VERSION 5.7 ;
  NOWIREEXTENSIONATPIN ON ;
  DIVIDERCHAR "/" ;
  BUSBITCHARS "[]" ;
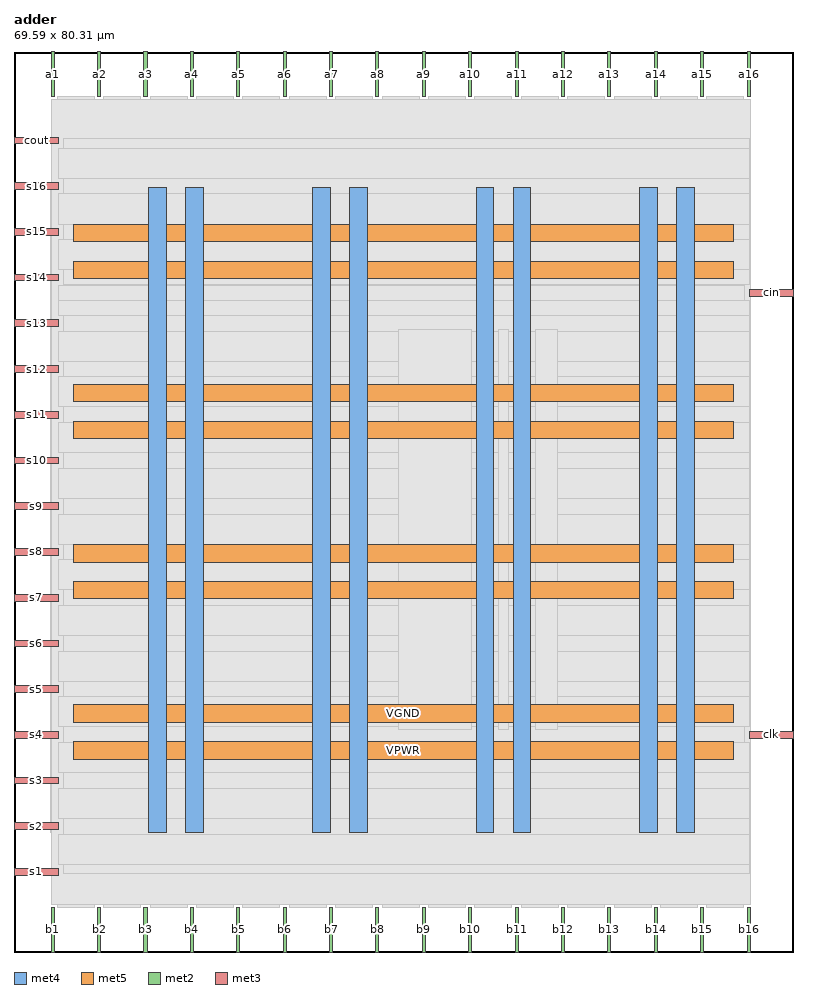
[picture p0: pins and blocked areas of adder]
MACRO adder
  CLASS BLOCK ;
  FOREIGN adder ;
  ORIGIN 0.000 0.000 ;
  SIZE 69.590 BY 80.310 ;
  PIN VGND
    DIRECTION INOUT ;
    USE GROUND ;
    PORT
      LAYER met4 ;
        RECT 15.320 10.640 16.920 68.240 ;
    END
    PORT
      LAYER met4 ;
        RECT 29.925 10.640 31.525 68.240 ;
    END
    PORT
      LAYER met4 ;
        RECT 44.530 10.640 46.130 68.240 ;
    END
    PORT
      LAYER met4 ;
        RECT 59.135 10.640 60.735 68.240 ;
    END
    PORT
      LAYER met5 ;
        RECT 5.280 20.520 64.180 22.120 ;
    END
    PORT
      LAYER met5 ;
        RECT 5.280 34.800 64.180 36.400 ;
    END
    PORT
      LAYER met5 ;
        RECT 5.280 49.080 64.180 50.680 ;
    END
    PORT
      LAYER met5 ;
        RECT 5.280 63.360 64.180 64.960 ;
    END
  END VGND
  PIN VPWR
    DIRECTION INOUT ;
    USE POWER ;
    PORT
      LAYER met4 ;
        RECT 12.020 10.640 13.620 68.240 ;
    END
    PORT
      LAYER met4 ;
        RECT 26.625 10.640 28.225 68.240 ;
    END
    PORT
      LAYER met4 ;
        RECT 41.230 10.640 42.830 68.240 ;
    END
    PORT
      LAYER met4 ;
        RECT 55.835 10.640 57.435 68.240 ;
    END
    PORT
      LAYER met5 ;
        RECT 5.280 17.220 64.180 18.820 ;
    END
    PORT
      LAYER met5 ;
        RECT 5.280 31.500 64.180 33.100 ;
    END
    PORT
      LAYER met5 ;
        RECT 5.280 45.780 64.180 47.380 ;
    END
    PORT
      LAYER met5 ;
        RECT 5.280 60.060 64.180 61.660 ;
    END
  END VPWR
  PIN a1
    DIRECTION INPUT ;
    USE SIGNAL ;
    ANTENNAGATEAREA 0.196500 ;
    PORT
      LAYER met2 ;
        RECT 3.310 76.310 3.590 80.310 ;
    END
  END a1
  PIN a10
    DIRECTION INPUT ;
    USE SIGNAL ;
    ANTENNAGATEAREA 0.196500 ;
    PORT
      LAYER met2 ;
        RECT 40.570 76.310 40.850 80.310 ;
    END
  END a10
  PIN a11
    DIRECTION INPUT ;
    USE SIGNAL ;
    ANTENNAGATEAREA 0.196500 ;
    PORT
      LAYER met2 ;
        RECT 44.710 76.310 44.990 80.310 ;
    END
  END a11
  PIN a12
    DIRECTION INPUT ;
    USE SIGNAL ;
    ANTENNAGATEAREA 0.196500 ;
    PORT
      LAYER met2 ;
        RECT 48.850 76.310 49.130 80.310 ;
    END
  END a12
  PIN a13
    DIRECTION INPUT ;
    USE SIGNAL ;
    ANTENNAGATEAREA 0.196500 ;
    PORT
      LAYER met2 ;
        RECT 52.990 76.310 53.270 80.310 ;
    END
  END a13
  PIN a14
    DIRECTION INPUT ;
    USE SIGNAL ;
    ANTENNAGATEAREA 0.196500 ;
    PORT
      LAYER met2 ;
        RECT 57.130 76.310 57.410 80.310 ;
    END
  END a14
  PIN a15
    DIRECTION INPUT ;
    USE SIGNAL ;
    ANTENNAGATEAREA 0.196500 ;
    PORT
      LAYER met2 ;
        RECT 61.270 76.310 61.550 80.310 ;
    END
  END a15
  PIN a16
    DIRECTION INPUT ;
    USE SIGNAL ;
    ANTENNAGATEAREA 0.196500 ;
    PORT
      LAYER met2 ;
        RECT 65.410 76.310 65.690 80.310 ;
    END
  END a16
  PIN a2
    DIRECTION INPUT ;
    USE SIGNAL ;
    ANTENNAGATEAREA 0.196500 ;
    PORT
      LAYER met2 ;
        RECT 7.450 76.310 7.730 80.310 ;
    END
  END a2
  PIN a3
    DIRECTION INPUT ;
    USE SIGNAL ;
    ANTENNAGATEAREA 0.196500 ;
    PORT
      LAYER met2 ;
        RECT 11.590 76.310 11.870 80.310 ;
    END
  END a3
  PIN a4
    DIRECTION INPUT ;
    USE SIGNAL ;
    ANTENNAGATEAREA 0.196500 ;
    PORT
      LAYER met2 ;
        RECT 15.730 76.310 16.010 80.310 ;
    END
  END a4
  PIN a5
    DIRECTION INPUT ;
    USE SIGNAL ;
    ANTENNAGATEAREA 0.196500 ;
    PORT
      LAYER met2 ;
        RECT 19.870 76.310 20.150 80.310 ;
    END
  END a5
  PIN a6
    DIRECTION INPUT ;
    USE SIGNAL ;
    ANTENNAGATEAREA 0.196500 ;
    PORT
      LAYER met2 ;
        RECT 24.010 76.310 24.290 80.310 ;
    END
  END a6
  PIN a7
    DIRECTION INPUT ;
    USE SIGNAL ;
    ANTENNAGATEAREA 0.196500 ;
    PORT
      LAYER met2 ;
        RECT 28.150 76.310 28.430 80.310 ;
    END
  END a7
  PIN a8
    DIRECTION INPUT ;
    USE SIGNAL ;
    ANTENNAGATEAREA 0.196500 ;
    PORT
      LAYER met2 ;
        RECT 32.290 76.310 32.570 80.310 ;
    END
  END a8
  PIN a9
    DIRECTION INPUT ;
    USE SIGNAL ;
    ANTENNAGATEAREA 0.196500 ;
    PORT
      LAYER met2 ;
        RECT 36.430 76.310 36.710 80.310 ;
    END
  END a9
  PIN b1
    DIRECTION INPUT ;
    USE SIGNAL ;
    ANTENNAGATEAREA 0.196500 ;
    PORT
      LAYER met2 ;
        RECT 3.310 0.000 3.590 4.000 ;
    END
  END b1
  PIN b10
    DIRECTION INPUT ;
    USE SIGNAL ;
    ANTENNAGATEAREA 0.196500 ;
    PORT
      LAYER met2 ;
        RECT 40.570 0.000 40.850 4.000 ;
    END
  END b10
  PIN b11
    DIRECTION INPUT ;
    USE SIGNAL ;
    ANTENNAGATEAREA 0.196500 ;
    PORT
      LAYER met2 ;
        RECT 44.710 0.000 44.990 4.000 ;
    END
  END b11
  PIN b12
    DIRECTION INPUT ;
    USE SIGNAL ;
    ANTENNAGATEAREA 0.196500 ;
    PORT
      LAYER met2 ;
        RECT 48.850 0.000 49.130 4.000 ;
    END
  END b12
  PIN b13
    DIRECTION INPUT ;
    USE SIGNAL ;
    ANTENNAGATEAREA 0.196500 ;
    PORT
      LAYER met2 ;
        RECT 52.990 0.000 53.270 4.000 ;
    END
  END b13
  PIN b14
    DIRECTION INPUT ;
    USE SIGNAL ;
    ANTENNAGATEAREA 0.196500 ;
    PORT
      LAYER met2 ;
        RECT 57.130 0.000 57.410 4.000 ;
    END
  END b14
  PIN b15
    DIRECTION INPUT ;
    USE SIGNAL ;
    ANTENNAGATEAREA 0.196500 ;
    PORT
      LAYER met2 ;
        RECT 61.270 0.000 61.550 4.000 ;
    END
  END b15
  PIN b16
    DIRECTION INPUT ;
    USE SIGNAL ;
    ANTENNAGATEAREA 0.196500 ;
    PORT
      LAYER met2 ;
        RECT 65.410 0.000 65.690 4.000 ;
    END
  END b16
  PIN b2
    DIRECTION INPUT ;
    USE SIGNAL ;
    ANTENNAGATEAREA 0.196500 ;
    PORT
      LAYER met2 ;
        RECT 7.450 0.000 7.730 4.000 ;
    END
  END b2
  PIN b3
    DIRECTION INPUT ;
    USE SIGNAL ;
    ANTENNAGATEAREA 0.196500 ;
    PORT
      LAYER met2 ;
        RECT 11.590 0.000 11.870 4.000 ;
    END
  END b3
  PIN b4
    DIRECTION INPUT ;
    USE SIGNAL ;
    ANTENNAGATEAREA 0.196500 ;
    PORT
      LAYER met2 ;
        RECT 15.730 0.000 16.010 4.000 ;
    END
  END b4
  PIN b5
    DIRECTION INPUT ;
    USE SIGNAL ;
    ANTENNAGATEAREA 0.196500 ;
    PORT
      LAYER met2 ;
        RECT 19.870 0.000 20.150 4.000 ;
    END
  END b5
  PIN b6
    DIRECTION INPUT ;
    USE SIGNAL ;
    ANTENNAGATEAREA 0.196500 ;
    PORT
      LAYER met2 ;
        RECT 24.010 0.000 24.290 4.000 ;
    END
  END b6
  PIN b7
    DIRECTION INPUT ;
    USE SIGNAL ;
    ANTENNAGATEAREA 0.196500 ;
    PORT
      LAYER met2 ;
        RECT 28.150 0.000 28.430 4.000 ;
    END
  END b7
  PIN b8
    DIRECTION INPUT ;
    USE SIGNAL ;
    ANTENNAGATEAREA 0.196500 ;
    PORT
      LAYER met2 ;
        RECT 32.290 0.000 32.570 4.000 ;
    END
  END b8
  PIN b9
    DIRECTION INPUT ;
    USE SIGNAL ;
    ANTENNAGATEAREA 0.196500 ;
    PORT
      LAYER met2 ;
        RECT 36.430 0.000 36.710 4.000 ;
    END
  END b9
  PIN cin
    DIRECTION INPUT ;
    USE SIGNAL ;
    ANTENNAGATEAREA 0.196500 ;
    PORT
      LAYER met3 ;
        RECT 65.590 58.520 69.590 59.120 ;
    END
  END cin
  PIN clk
    DIRECTION INPUT ;
    USE SIGNAL ;
    ANTENNAGATEAREA 0.852000 ;
    PORT
      LAYER met3 ;
        RECT 65.590 19.080 69.590 19.680 ;
    END
  END clk
  PIN cout
    DIRECTION OUTPUT ;
    USE SIGNAL ;
    ANTENNADIFFAREA 0.340600 ;
    PORT
      LAYER met3 ;
        RECT 0.000 72.120 4.000 72.720 ;
    END
  END cout
  PIN s1
    DIRECTION OUTPUT ;
    USE SIGNAL ;
    ANTENNADIFFAREA 0.340600 ;
    PORT
      LAYER met3 ;
        RECT 0.000 6.840 4.000 7.440 ;
    END
  END s1
  PIN s10
    DIRECTION OUTPUT ;
    USE SIGNAL ;
    ANTENNADIFFAREA 0.340600 ;
    PORT
      LAYER met3 ;
        RECT 0.000 43.560 4.000 44.160 ;
    END
  END s10
  PIN s11
    DIRECTION OUTPUT ;
    USE SIGNAL ;
    ANTENNADIFFAREA 0.340600 ;
    PORT
      LAYER met3 ;
        RECT 0.000 47.640 4.000 48.240 ;
    END
  END s11
  PIN s12
    DIRECTION OUTPUT ;
    USE SIGNAL ;
    ANTENNADIFFAREA 0.340600 ;
    PORT
      LAYER met3 ;
        RECT 0.000 51.720 4.000 52.320 ;
    END
  END s12
  PIN s13
    DIRECTION OUTPUT ;
    USE SIGNAL ;
    ANTENNADIFFAREA 0.340600 ;
    PORT
      LAYER met3 ;
        RECT 0.000 55.800 4.000 56.400 ;
    END
  END s13
  PIN s14
    DIRECTION OUTPUT ;
    USE SIGNAL ;
    ANTENNADIFFAREA 0.340600 ;
    PORT
      LAYER met3 ;
        RECT 0.000 59.880 4.000 60.480 ;
    END
  END s14
  PIN s15
    DIRECTION OUTPUT ;
    USE SIGNAL ;
    ANTENNADIFFAREA 0.340600 ;
    PORT
      LAYER met3 ;
        RECT 0.000 63.960 4.000 64.560 ;
    END
  END s15
  PIN s16
    DIRECTION OUTPUT ;
    USE SIGNAL ;
    ANTENNADIFFAREA 0.340600 ;
    PORT
      LAYER met3 ;
        RECT 0.000 68.040 4.000 68.640 ;
    END
  END s16
  PIN s2
    DIRECTION OUTPUT ;
    USE SIGNAL ;
    ANTENNADIFFAREA 0.340600 ;
    PORT
      LAYER met3 ;
        RECT 0.000 10.920 4.000 11.520 ;
    END
  END s2
  PIN s3
    DIRECTION OUTPUT ;
    USE SIGNAL ;
    ANTENNADIFFAREA 0.340600 ;
    PORT
      LAYER met3 ;
        RECT 0.000 15.000 4.000 15.600 ;
    END
  END s3
  PIN s4
    DIRECTION OUTPUT ;
    USE SIGNAL ;
    ANTENNADIFFAREA 0.340600 ;
    PORT
      LAYER met3 ;
        RECT 0.000 19.080 4.000 19.680 ;
    END
  END s4
  PIN s5
    DIRECTION OUTPUT ;
    USE SIGNAL ;
    ANTENNADIFFAREA 0.340600 ;
    PORT
      LAYER met3 ;
        RECT 0.000 23.160 4.000 23.760 ;
    END
  END s5
  PIN s6
    DIRECTION OUTPUT ;
    USE SIGNAL ;
    ANTENNADIFFAREA 0.340600 ;
    PORT
      LAYER met3 ;
        RECT 0.000 27.240 4.000 27.840 ;
    END
  END s6
  PIN s7
    DIRECTION OUTPUT ;
    USE SIGNAL ;
    ANTENNADIFFAREA 0.340600 ;
    PORT
      LAYER met3 ;
        RECT 0.000 31.320 4.000 31.920 ;
    END
  END s7
  PIN s8
    DIRECTION OUTPUT ;
    USE SIGNAL ;
    ANTENNADIFFAREA 0.340600 ;
    PORT
      LAYER met3 ;
        RECT 0.000 35.400 4.000 36.000 ;
    END
  END s8
  PIN s9
    DIRECTION OUTPUT ;
    USE SIGNAL ;
    ANTENNADIFFAREA 0.340600 ;
    PORT
      LAYER met3 ;
        RECT 0.000 39.480 4.000 40.080 ;
    END
  END s9
  OBS
      LAYER nwell ;
        RECT 5.330 10.795 64.130 68.190 ;
      LAYER li1 ;
        RECT 5.520 10.795 63.940 68.085 ;
      LAYER met1 ;
        RECT 3.290 10.640 65.710 68.240 ;
      LAYER met2 ;
        RECT 3.870 76.030 7.170 76.310 ;
        RECT 8.010 76.030 11.310 76.310 ;
        RECT 12.150 76.030 15.450 76.310 ;
        RECT 16.290 76.030 19.590 76.310 ;
        RECT 20.430 76.030 23.730 76.310 ;
        RECT 24.570 76.030 27.870 76.310 ;
        RECT 28.710 76.030 32.010 76.310 ;
        RECT 32.850 76.030 36.150 76.310 ;
        RECT 36.990 76.030 40.290 76.310 ;
        RECT 41.130 76.030 44.430 76.310 ;
        RECT 45.270 76.030 48.570 76.310 ;
        RECT 49.410 76.030 52.710 76.310 ;
        RECT 53.550 76.030 56.850 76.310 ;
        RECT 57.690 76.030 60.990 76.310 ;
        RECT 61.830 76.030 65.130 76.310 ;
        RECT 3.320 4.280 65.680 76.030 ;
        RECT 3.870 4.000 7.170 4.280 ;
        RECT 8.010 4.000 11.310 4.280 ;
        RECT 12.150 4.000 15.450 4.280 ;
        RECT 16.290 4.000 19.590 4.280 ;
        RECT 20.430 4.000 23.730 4.280 ;
        RECT 24.570 4.000 27.870 4.280 ;
        RECT 28.710 4.000 32.010 4.280 ;
        RECT 32.850 4.000 36.150 4.280 ;
        RECT 36.990 4.000 40.290 4.280 ;
        RECT 41.130 4.000 44.430 4.280 ;
        RECT 45.270 4.000 48.570 4.280 ;
        RECT 49.410 4.000 52.710 4.280 ;
        RECT 53.550 4.000 56.850 4.280 ;
        RECT 57.690 4.000 60.990 4.280 ;
        RECT 61.830 4.000 65.130 4.280 ;
      LAYER met3 ;
        RECT 4.400 71.720 65.590 72.585 ;
        RECT 3.990 69.040 65.590 71.720 ;
        RECT 4.400 67.640 65.590 69.040 ;
        RECT 3.990 64.960 65.590 67.640 ;
        RECT 4.400 63.560 65.590 64.960 ;
        RECT 3.990 60.880 65.590 63.560 ;
        RECT 4.400 59.520 65.590 60.880 ;
        RECT 4.400 59.480 65.190 59.520 ;
        RECT 3.990 58.120 65.190 59.480 ;
        RECT 3.990 56.800 65.590 58.120 ;
        RECT 4.400 55.400 65.590 56.800 ;
        RECT 3.990 52.720 65.590 55.400 ;
        RECT 4.400 51.320 65.590 52.720 ;
        RECT 3.990 48.640 65.590 51.320 ;
        RECT 4.400 47.240 65.590 48.640 ;
        RECT 3.990 44.560 65.590 47.240 ;
        RECT 4.400 43.160 65.590 44.560 ;
        RECT 3.990 40.480 65.590 43.160 ;
        RECT 4.400 39.080 65.590 40.480 ;
        RECT 3.990 36.400 65.590 39.080 ;
        RECT 4.400 35.000 65.590 36.400 ;
        RECT 3.990 32.320 65.590 35.000 ;
        RECT 4.400 30.920 65.590 32.320 ;
        RECT 3.990 28.240 65.590 30.920 ;
        RECT 4.400 26.840 65.590 28.240 ;
        RECT 3.990 24.160 65.590 26.840 ;
        RECT 4.400 22.760 65.590 24.160 ;
        RECT 3.990 20.080 65.590 22.760 ;
        RECT 4.400 18.680 65.190 20.080 ;
        RECT 3.990 16.000 65.590 18.680 ;
        RECT 4.400 14.600 65.590 16.000 ;
        RECT 3.990 11.920 65.590 14.600 ;
        RECT 4.400 10.520 65.590 11.920 ;
        RECT 3.990 7.840 65.590 10.520 ;
        RECT 4.400 6.975 65.590 7.840 ;
      LAYER met4 ;
        RECT 34.335 19.895 40.830 55.585 ;
        RECT 43.230 19.895 44.130 55.585 ;
        RECT 46.530 19.895 48.465 55.585 ;
  END
END adder
END LIBRARY

